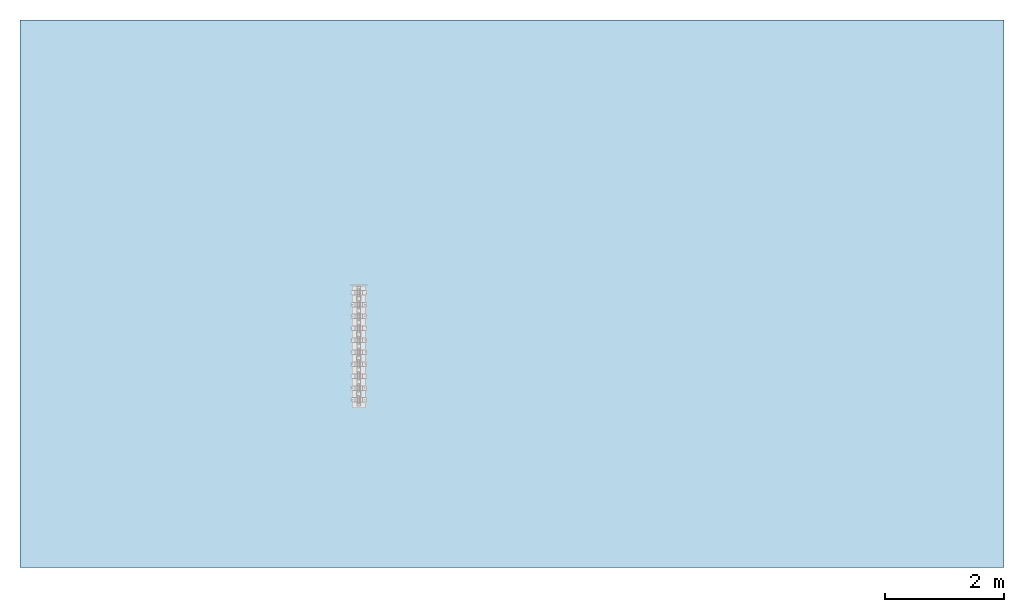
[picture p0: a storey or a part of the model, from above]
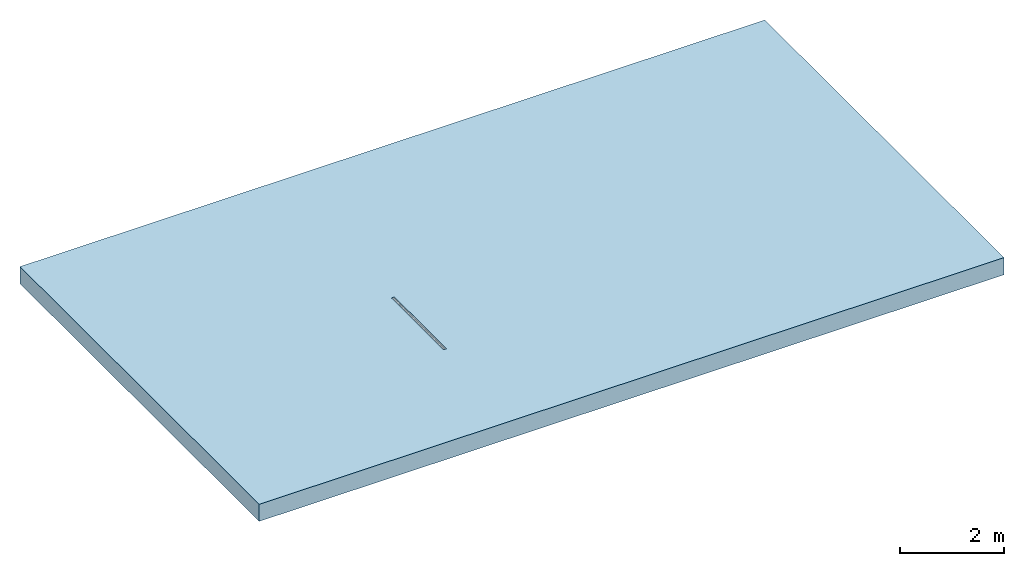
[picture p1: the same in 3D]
Properties of the parts of a building model (IFC2X3)

# File
Description: ViewDefinition [CoordinationView]
File name: 32800 - Q-Flow Edge - D.I.ifc
Time: 2013-09-04T16:49:34
Written by: Autodesk Revit 2013
Made in: 20120221_2030(x64)

# IfcProject, Project Number
LongName: Project Name; Phase: Project Status

# IfcSite, Default
RefLatitude: 42, 21, 30, 344238; RefLongitude: -71, -3, -35, -194702; RefElevation: 0 mm

# IfcBuilding
Pset_BuildingCommon - NumberOfStoreys: 1
Other - Client Name: Owner; Project Address: ## Street City, State Zip; Project Name: Project Name; Project Number: Project Number; Project Status: Project Status; Project Issue Date: Issue Date

# IfcBuildingStorey, Level 1
LongName: Level 1; Elevation: 0 mm
Graphics - Line Weight: 1; Symbol: M_Level Head - Circle: M_Level Head - Circle; Line Pattern: Center; Symbol at End 1 Default: no; Color: 0; Symbol at End 2 Default: yes
Constraints - Elevation Base: 0; Elevation: 0 mm
Identity Data - Name: Level 1; Building Story: yes; Structural: no
Dimensions - Computation Height: 0 mm

# IfcFlowTerminal: 32800 - Q-Flow Edge - D.I, Qmax 225:32800 - Q-Flow Edge - D.I:32800 - Q-Flow Edge - D.I:351197
In: Level 1
Constraints - Level: Level: Level 1; Moves With Nearby Elements: no
Construction - 32995_150-225 Step Connector: no; 42221_225 End Cap (at Female end): no; 42221_225 End Cap (at Male end): no; E3-QFlow-GalvSteel: no; E2-QGuard-DuctileIron: no; E4-QGuard-GalvSteel: no; E5-QSlot-GalvSteel: no; E1-QFlow-DuctileIron: yes; V_Coarse_E5: no; V_CoarseE1: yes
Identity Data - Mark: 62; Fax: +44 (0)1462 815895; Manufacturer: ACO Technologies plc - ACO Water Management Division; Assembly Code: D2040; Product Brochure: http://www.aco.co.uk/download.php?id=220; Product Code: 32800; e-mail Sales: customersupport@aco.co.uk; OmniClass Title: Rainwater Removal; OmniClass Number: 23.70.50.24; Model: ACO Qmax 225; URL: www.aco.co.uk; Assembly Description: Rain Water Drainage; Price: POA - contact ACO; Telephone: +44 (0)1462 816666; Maintenance Guidelines: http://www.aco.co.uk/download.php?id=220; Address: ACO Business Park, Hitchin Road, Shefford, Bedfordshire, United Kingdom SG17 5TE; Installation Guidelines: http://www.aco.co.uk/download.php?id=220; Type Comments: ACO Qmax 225 channel assembly complete with ACO Q-Flow ductile iron edge rail; Product Page URL: http://www.aco.co.uk/product_detail.php?id=79; Model Description: High capacity slot drainage channel system; e-mail Technical: technical@aco.co.uk; Cost: 0
Phasing - Phase Created: New Construction
Green Building Properties - Seal Recyclable: Fully recyclable; Channel Recyclable: Fully recyclable; Edge Rail Recycled Material Content: Between 40% - 90%; Channel Recycled Material Content: Variable %; Seal Recycled Material Content: 0%; Edge Rail Recyclable: Fully recyclable
Data - Product Weight: 24kg; Installation - Concrete Grade: Refer to brochure; Hydraulic Performance: http://www.aco.co.uk/download.php?id=220; Invert Depth: 425mm; Load Class: A 15 - F 900; Product Standard: BS EN 1433:2002 CE marked; Drainage Slot Intake Area: 18775mm²/m; Drainage Slot Width: 26mm; Concrete Surround Volume - Load Class F 900: 0.345 m³/m; ACO Hydraulic Design Software: http://www.acodesign.co.uk; Product Dimensions: 2000mm x 290mm x 480mm (LxWxH); Concrete Surround Volume - Load Class A 15 - E 600: 0.255 m³/m; Channel C.S.A: 39761mm²; Installation - Reinforcement Details: Refer to brochure
General - TagNumber: 0; SerialNumber: 0
Materials and Finishes - Edge Rail Colour: Black; Seal Material: Chloroprene; Edge Rail Material: Ductile Iron; Seal Colour: Black; Channel Material: Medium Density Polyethylene; Edge Rail Finish: ATec coating; Channel Colour: Black
Model Properties - Multi-functional End Cap - Channel Colour: Black; 150-225 Step Connector - Recyclable: Fully recyclable; Multi-functional End Cap - Seal Recyclable: Fully recyclable; Multi-functional End Cap - Weight: 1.4 kg; Multi-functional End Cap - Dimensions: Ø290mm x 240mm (ØxL); 150-225 Step Connector - Recycled Material Content: 0%; Multi-functional End Cap - Seal Material: Chloroprene; 150-225 Step Connector - Colour: Black; 150-225 Step Connector - Dimensions: Ø310mm x 25mm (ØxL); 150-225 Step Connector - Product Code: 32995; 150-225 Step Connector - Material: High Density Polyethylene; Multi-functional End Cap - Product Code: 42221; Multi-functional End Cap - Seal Recycled Material Content: 0%; Multi-functional End Cap - Channel Recycled Material Content: Variable %; 150-225 Step Connector - Model Description: High capacity slot drainage channel system; Multi-functional End Cap - Channel Material: Medium Density Polyethylene; Multi-functional End Cap - Seal Colour: Black; Multi-functional End Cap - Model Description: High capacity slot drainage channel system; 150-225 Step Connector - Weight: 0.4 kg; Multi-functional End Cap - Channel Recyclable: Fully recyclable
Other - Created by: www.aco.co.uk; Revision: 1
Dimensions - BoreCentre: 311.5 mm; Width Overall: 290 mm; Depth Overall: 480 mm; Length: 2000 mm; Floor Opening Width: 65 mm

# IfcOpeningElement: Opening
In: Level 1
Constraints - Related to Mass: no; Level: Level: Level 1; Height Offset From Level: 0 mm; Room Bounding: yes
Structural - Structural: no; Enable Analytical Model: no
Phasing - Phase Created: New Construction
Dimensions - Area: 151340000 mm2; Thickness: 400 mm; Volume: 60351000000 mm3; Perimeter: 51360 mm
Analytical Properties - Absorptance: 0.1; Roughness: 1
Construction - Function: 0; Default Thickness: 400 mm
Graphics - Coarse Scale Fill Color: 0
Materials and Finishes - Structural Material: Plant

# IfcSlab: Floor:Generic Floor - 400mm, Floor:Generic Floor - 400mm:193825
In: Level 1
PredefinedType: FLOOR; Material: Plant 400 mm
Constraints - Related to Mass: no; Level: Level: Level 1; Height Offset From Level: 0 mm; Room Bounding: yes
Structural - Structural: no; Enable Analytical Model: no
Phasing - Phase Created: New Construction
Dimensions - Area: 151340000 mm2; Thickness: 400 mm; Volume: 60351000000 mm3; Perimeter: 51360 mm
Pset_SlabCommon - Reference: Generic Floor - 400mm; IsExternal: no; LoadBearing: yes
Analytical Properties - Absorptance: 0.1; Roughness: 1
Construction - Function: 0; Default Thickness: 400 mm
Graphics - Coarse Scale Fill Color: 0
Materials and Finishes - Structural Material: Plant
